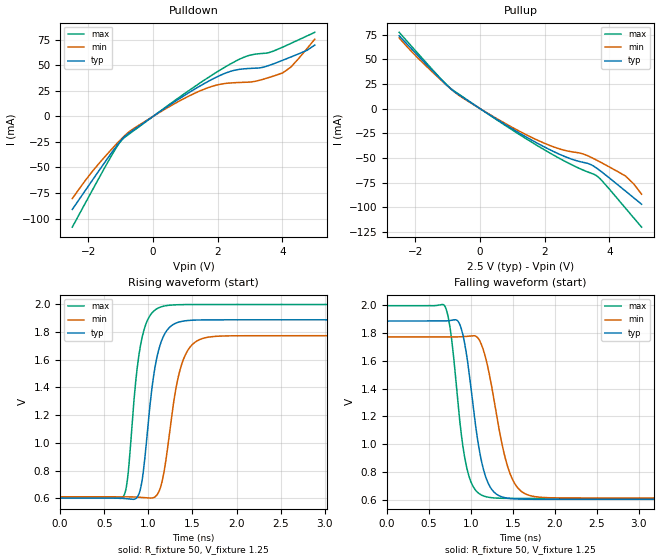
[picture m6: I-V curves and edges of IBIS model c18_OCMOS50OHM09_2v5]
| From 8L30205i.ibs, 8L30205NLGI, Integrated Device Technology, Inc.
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[Model] c18_OCMOS50OHM09_2v5
Model_type   Output
Polarity   Non-Inverting
|   typ   min   max
C_comp   2pF   1.5pF   2.5pF
Vmeas = 1.25V
Rref = 50
Cref = 0
Vref = 1.25V
|   typ   min   max
[Voltage range]   2.5V   2.375V   2.625V
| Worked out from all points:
|   slope of the pulldown table from 0 to 0.375 V, typ, clamps not added: 46 ohm
|   slope of the pullup table from 0 to 0.375 V, typ, clamps not added: 47.6 ohm
|   rising waveform, R_fixture 50, V_fixture 1.25: 20-80 % time 147ps typ, 174ps min, 130ps max; typ from 0.602 V to 1.89 V
|   falling waveform, R_fixture 50, V_fixture 1.25: 20-80 % time 181ps typ, 228ps min, 154ps max; typ from 1.89 V to 0.602 V
[Pulldown]
|Voltage   I (typ)   I (min)   I (max)
-2.5V     -91.06mA   -80.45mA   -108.4mA
-1.9V     -63.46mA   -54.63mA   -73.44mA
-1.249V   -34.06mA   -30.97mA   -36.42mA
-887.7mV  -20.02mA   -19.09mA   -20.76mA
738.5mV   15.8mA     13.77mA    17.04mA
1.943V    38.13mA    30.46mA    42.82mA
2.425V    44.37mA    32.76mA    51.87mA
2.847V    46.61mA    33.38mA    58.34mA
3.389V    47.98mA    36.18mA    61.61mA
4.008V    54.89mA    42.54mA    67.77mA
4.256V    58.02mA    48.07mA    71.32mA
5V        69.78mA    75.52mA    82.25mA
[Pullup]
|Voltage   I (typ)   I (min)   I (max)
-2.5V     73.73mA    71.6mA     77.21mA
-1.9V     53.01mA    50.58mA    55.1mA
-1.068V   25.1mA     24.74mA    25.35mA
-526.3mV  11.26mA    10.67mA    11.72mA
738.5mV   -15.31mA   -14.26mA   -16.1mA
1.762V    -34.85mA   -31.74mA   -37.25mA
2.545V    -47.46mA   -41.62mA   -51.94mA
3.148V    -54.11mA   -45.54mA   -61.63mA
3.63V     -60.79mA   -52.55mA   -68.51mA
4.504V    -83.57mA   -68.34mA   -100.9mA
4.752V    -90.21mA   -76.16mA   -110.5mA
5V        -96.84mA   -86.67mA   -120mA
[Ramp]
|   typ   min   max
dV/dt_r   0.776/0.147n   0.702/0.175n   0.838/0.13n
dV/dt_f   0.776/0.181n   0.702/0.229n   0.839/0.154n
R_load =   50.0000
[Rising Waveform]
R_fixture = 50
V_fixture = 1.25   |Vcc_typ
V_fixture_min = 1.1875 |Vcc_min
V_fixture_max = 1.3125 |Vcc_max
C_fixture = 0.0p
| Time   typ   min   max
0s        602mV      611.4mV    608.3mV
722.7ps   599.1mV    611.3mV    619.8mV
770.3ps   596.4mV    610.9mV    777.6mV
874.9ps   609.5mV    608.7mV    1.547V
979.5ps   1.014V     604mV      1.869V
1.065ns   1.506V     606.9mV    1.953V
1.17ns    1.767V     763.3mV    1.986V
1.379ns   1.877V     1.569V     1.997V
1.664ns   1.887V     1.761V     1.998V
9.49ns    1.888V     1.773V     1.998V
[Falling Waveform]
R_fixture = 50
V_fixture = 1.25   |Vcc_typ
V_fixture_min = 1.1875 |Vcc_min
V_fixture_max = 1.3125 |Vcc_max
C_fixture = 0.0p
| Time   typ   min   max
0s        1.888V     1.773V     1.998V
684.7ps   1.888V     1.773V     1.998V
760.8ps   1.892V     1.773V     1.797V
855.9ps   1.876V     1.774V     1.227V
979.5ps   1.504V     1.779V     761.5mV
1.084ns   1.011V     1.764V     649.2mV
1.179ns   756.2mV    1.61V      620.7mV
1.455ns   608.6mV    803.8mV    608.7mV
1.74ns    602.3mV    623.6mV    608.3mV
9.49ns    602mV      611.4mV    608.3mV
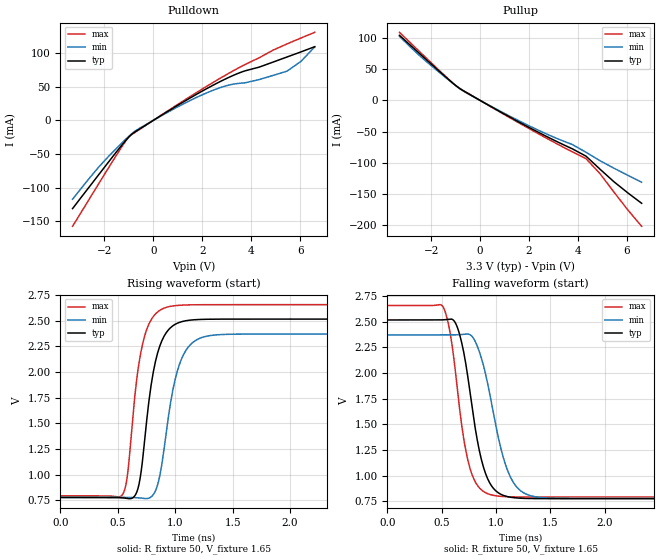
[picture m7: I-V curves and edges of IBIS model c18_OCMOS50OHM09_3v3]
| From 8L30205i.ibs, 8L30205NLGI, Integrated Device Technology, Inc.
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[Model] c18_OCMOS50OHM09_3v3
Model_type   Output
Polarity   Non-Inverting
|   typ   min   max
C_comp   2pF   1.5pF   2.5pF
Vmeas = 1.65V
Rref = 50
Cref = 0
Vref = 1.65V
|   typ   min   max
[Voltage range]   3.3V   3.135V   3.465V
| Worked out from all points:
|   slope of the pulldown table from 0 to 0.495 V, typ, clamps not added: 44 ohm
|   slope of the pullup table from 0 to 0.495 V, typ, clamps not added: 45 ohm
|   rising waveform, R_fixture 50, V_fixture 1.65: 20-80 % time 129ps typ, 147ps min, 118ps max; typ from 0.775 V to 2.52 V
|   falling waveform, R_fixture 50, V_fixture 1.65: 20-80 % time 165ps typ, 201ps min, 144ps max; typ from 2.52 V to 0.775 V
[Pulldown]
|Voltage   I (typ)   I (min)   I (max)
-3.3V     -131.2mA   -117.2mA   -157.5mA
-2.22V    -80.21mA   -68.94mA   -93.54mA
-1.309V   -37.85mA   -34.53mA   -40.5mA
-947.9mV  -22.78mA   -22.01mA   -23.03mA
618mV     13.99mA    12.64mA    14.73mA
2.304V    49.56mA    42.73mA    53.3mA
2.967V    61.82mA    51.27mA    67.49mA
3.509V    70.48mA    55.05mA    78.46mA
4.328V    79.16mA    60.67mA    93.05mA
5.464V    94.18mA    73.13mA    113.6mA
6.032V    101.7mA    87.58mA    122.3mA
6.6V      109.5mA    109.2mA    130.9mA
[Pullup]
|Voltage   I (typ)   I (min)   I (max)
-3.3V     104.4mA    102.8mA    109.3mA
-2.22V    66.05mA    63.06mA    68.6mA
-1.249V   32.2mA     31.61mA    32.6mA
-887.7mV  20.54mA    20.57mA    20.69mA
-466.1mV  10.47mA    10.03mA    10.79mA
1.401V    -30.69mA   -29mA      -31.89mA
2.666V    -56.79mA   -52.88mA   -59.57mA
3.76V     -77.41mA   -70.55mA   -82.26mA
4.328V    -89.37mA   -83.08mA   -93.43mA
4.896V    -110.1mA   -96.57mA   -117.3mA
5.464V    -130.2mA   -108.6mA   -146.7mA
6.6V      -164.9mA   -131.2mA   -201.8mA
[Ramp]
|   typ   min   max
dV/dt_r   1.051/0.128n   0.963/0.148n   1.125/0.118n
dV/dt_f   1.05/0.165n   0.962/0.202n   1.124/0.144n
R_load =   50.0000
[Rising Waveform]
R_fixture = 50
V_fixture = 1.65   |Vcc_typ
V_fixture_min = 1.5675 |Vcc_min
V_fixture_max = 1.7325 |Vcc_max
C_fixture = 0.0p
| Time   typ   min   max
0s        775.4mV    777.5mV    791.5mV
542ps     771.7mV    777.8mV    807.1mV
589.6ps   765.1mV    777.3mV    1.051V
646.6ps   790.7mV    774.6mV    1.755V
722.7ps   1.218V     767.2mV    2.308V
836.8ps   2.147V     867.5mV    2.577V
970ps     2.444V     1.772V     2.644V
1.113ns   2.505V     2.243V     2.656V
1.379ns   2.517V     2.365V     2.658V
9.49ns    2.517V     2.371V     2.658V
[Falling Waveform]
R_fixture = 50
V_fixture = 1.65   |Vcc_typ
V_fixture_min = 1.5675 |Vcc_min
V_fixture_max = 1.7325 |Vcc_max
C_fixture = 0.0p
| Time   typ   min   max
0s        2.517V     2.371V     2.658V
504ps     2.518V     2.371V     2.657V
618.1ps   2.503V     2.372V     2.096V
694.2ps   2.251V     2.377V     1.424V
760.8ps   1.818V     2.374V     1.072V
865.4ps   1.161V     2.148V     862.2mV
979.5ps   873mV      1.594V     807mV
1.151ns   787mV      951.8mV    793.1mV
1.426ns   775.8mV    785.9mV    791.6mV
9.49ns    775.4mV    777.5mV    791.5mV
